One B-rep face of a CAD part: STEP entity #1399.
In plain terms, the planar face has unit normal (1, 0, 0).
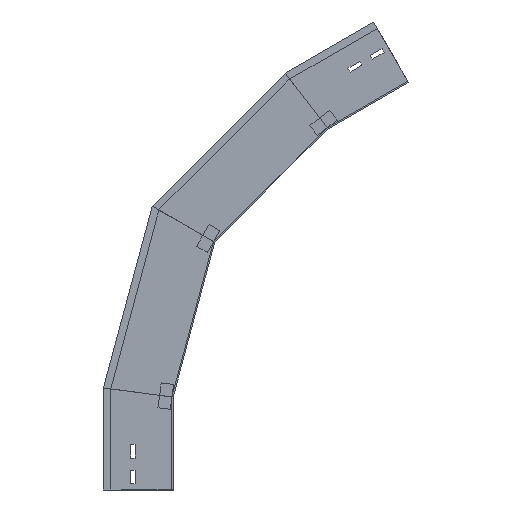
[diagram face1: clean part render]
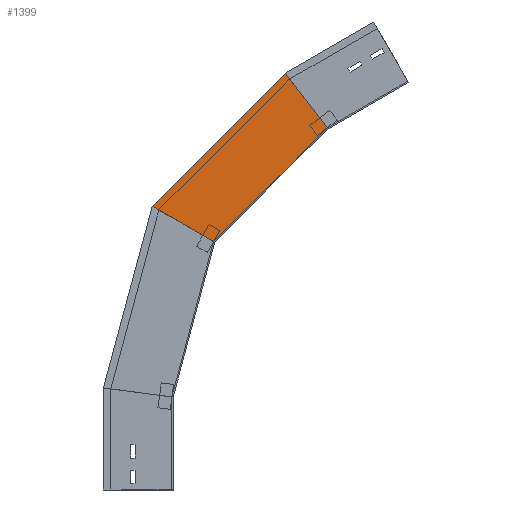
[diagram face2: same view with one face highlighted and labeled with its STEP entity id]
Its self-contained STEP definition (entity closure, numbers rounded to 3 decimals):
#55 = LINE ( 'NONE', #1588, #889 ) ;
#77 = DIRECTION ( 'NONE',  ( 0., -0.991, -0.131 ) ) ;
#99 = DIRECTION ( 'NONE',  ( 1., 0., 0. ) ) ;
#125 = CARTESIAN_POINT ( 'NONE',  ( 0., 4.243, 134.167 ) ) ;
#170 = CARTESIAN_POINT ( 'NONE',  ( 0., 112.5, 164.811 ) ) ;
#223 = DIRECTION ( 'NONE',  ( 0., -0.259, 0.966 ) ) ;
#224 = VERTEX_POINT ( 'NONE', #272 ) ;
#272 = CARTESIAN_POINT ( 'NONE',  ( 0., -67.034, 400.175 ) ) ;
#445 = LINE ( 'NONE', #1456, #1111 ) ;
#465 = ORIENTED_EDGE ( 'NONE', *, *, #590, .T. ) ;
#514 = VECTOR ( 'NONE', #223, 1000. ) ;
#557 = VERTEX_POINT ( 'NONE', #1211 ) ;
#590 = EDGE_CURVE ( 'NONE', #763, #557, #55, .T. ) ;
#732 = AXIS2_PLACEMENT_3D ( 'NONE', #125, #99, #1018 ) ;
#763 = VERTEX_POINT ( 'NONE', #170 ) ;
#765 = FACE_OUTER_BOUND ( 'NONE', #1541, .T. ) ;
#774 = EDGE_CURVE ( 'NONE', #557, #224, #445, .T. ) ;
#847 = CARTESIAN_POINT ( 'NONE',  ( 0., -19.411, 147.444 ) ) ;
#889 = VECTOR ( 'NONE', #1198, 1000. ) ;
#891 = VERTEX_POINT ( 'NONE', #1425 ) ;
#1018 = DIRECTION ( 'NONE',  ( 0., 0., -1. ) ) ;
#1031 = VECTOR ( 'NONE', #77, 1000. ) ;
#1111 = VECTOR ( 'NONE', #1327, 1000. ) ;
#1198 = DIRECTION ( 'NONE',  ( 0., -0.259, 0.966 ) ) ;
#1211 = CARTESIAN_POINT ( 'NONE',  ( 0., 33.831, 458.409 ) ) ;
#1218 = EDGE_CURVE ( 'NONE', #763, #891, #1623, .T. ) ;
#1270 = CARTESIAN_POINT ( 'NONE',  ( 0., 4.243, 134.167 ) ) ;
#1327 = DIRECTION ( 'NONE',  ( 0., -0.866, -0.5 ) ) ;
#1386 = EDGE_CURVE ( 'NONE', #891, #224, #1673, .T. ) ;
#1399 = ADVANCED_FACE ( 'NONE', ( #765 ), #1407, .T. ) ;
#1407 = PLANE ( 'NONE',  #732 ) ;
#1425 = CARTESIAN_POINT ( 'NONE',  ( 0., 0., 150. ) ) ;
#1456 = CARTESIAN_POINT ( 'NONE',  ( 0., -128.762, 364.536 ) ) ;
#1501 = ORIENTED_EDGE ( 'NONE', *, *, #774, .T. ) ;
#1517 = ORIENTED_EDGE ( 'NONE', *, *, #1386, .F. ) ;
#1541 = EDGE_LOOP ( 'NONE', ( #465, #1501, #1517, #1646 ) ) ;
#1588 = CARTESIAN_POINT ( 'NONE',  ( 0., 112.909, 163.284 ) ) ;
#1623 = LINE ( 'NONE', #847, #1031 ) ;
#1646 = ORIENTED_EDGE ( 'NONE', *, *, #1218, .F. ) ;
#1673 = LINE ( 'NONE', #1270, #514 ) ;
